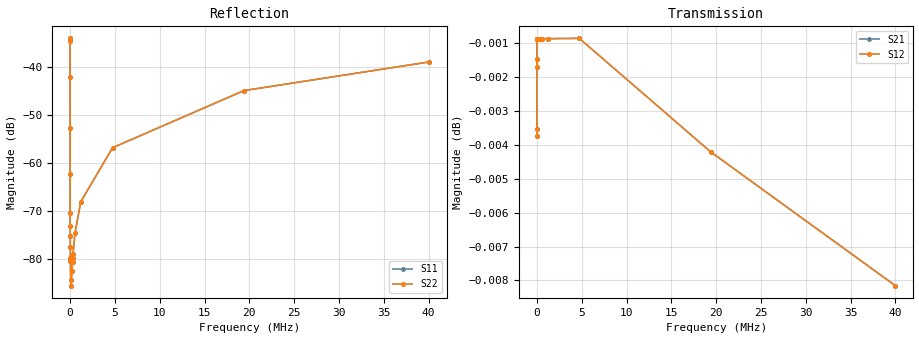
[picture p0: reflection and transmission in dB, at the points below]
! *  *** Spice model ***
! *  Copyright (C) Panasonic Industry
! *  Conductive Polymer Aluminum Solid Capacitors (OS-CON)
! *  Parts No. 6SVPT820M
! Touchstone file from project
# GHZ S RI R 50.000000
! Modal data exported
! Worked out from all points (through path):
!   450 points, 100 Hz to 40 MHz, reference 50 ohm
!   highest |S21| = 0.00 dB at 205.4 kHz (marker M1); lowest = 0.0 dB at 40 MHz (marker M2)
!   lowest |S11| = -85.5 dB at 100 kHz (marker M3), VSWR 1.00, Z = 50 + j0.000362 ohm
!   |S11| at or under -10 dB: start of sweep to end of sweep
!   |S22| runs from -85.5 to -34.1 dB; largest |S21 - S12| = 1e-10
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1e-07  0.000597 -0.0196  0.9994 0.0196  0.9994 0.0196  0.000597 -0.0196
1.059254e-07  0.000551 -0.0185  0.9994 0.0185  0.9994 0.0185  0.000551 -0.0185
2.511886e-07  0.000234 -0.00783  0.9998 0.00783  0.9998 0.00783  0.000234 -0.00783
8.659643e-07  0.000151 -0.0023  0.9998 0.0023  0.9998 0.0023  0.000151 -0.0023
2.73842e-06  0.000113 -0.000752  0.9999 0.000752  0.9999 0.000752  0.000113 -0.000752
7.498942e-06  8.82e-05 -0.000289  0.9999 0.000289  0.9999 0.000289  8.82e-05 -0.000289
1.059254e-05  8.25e-05 -0.000208  0.9999 0.000208  0.9999 0.000208  8.25e-05 -0.000208
1.453784e-05  7.8e-05 -0.000155  0.9999 0.000155  0.9999 0.000155  7.8e-05 -0.000155
2.053525e-05  7.3e-05 -0.000112  0.9999 0.000112  0.9999 0.000112  7.3e-05 -0.000112
2.985383e-05  6.7e-05 -7.74e-05  0.9999 7.74e-05  0.9999 7.74e-05  6.7e-05 -7.74e-05
3.254618e-05  6.56e-05 -7.05e-05  0.9999 7.05e-05  0.9999 7.05e-05  6.56e-05 -7.05e-05
6.493816e-05  5.62e-05 -2.32e-05  0.9999 2.32e-05  0.9999 2.32e-05  5.62e-05 -2.32e-05
0.0001  5.32e-05 3.62e-06  0.9999 -3.62e-06  0.9999 -3.62e-06  5.32e-05 3.62e-06
0.0002053525  5.17e-05 5.48e-05  0.9999 -5.48e-05  0.9999 -5.48e-05  5.17e-05 5.48e-05
0.0002660725  5.21e-05 7.88e-05  0.9999 -7.88e-05  0.9999 -7.88e-05  5.21e-05 7.88e-05
0.0002900681  5.23e-05 8.79e-05  0.9999 -8.79e-05  0.9999 -8.79e-05  5.23e-05 8.79e-05
0.0003254618  5.28e-05 0.000101  0.9999 -0.000101  0.9999 -0.000101  5.28e-05 0.000101
0.0005463865  5.67e-05 0.000179  0.9999 -0.000179  0.9999 -0.000179  5.67e-05 0.000179
0.001188502  7.48e-05 0.000389  0.9999 -0.000389  0.9999 -0.000389  7.48e-05 0.000389
0.004731513  0.000148 0.00143  0.9999 -0.00143  0.9999 -0.00143  0.000148 0.00143
0.01938653  0.000465 0.00561  0.9995 -0.00561  0.9995 -0.00561  0.000465 0.00561
0.04  0.00101 0.0111  0.999 -0.0111  0.999 -0.0111  0.00101 0.0111
